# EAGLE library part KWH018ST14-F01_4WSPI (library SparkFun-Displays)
Fomike KWH018ST14-F01 TFT LCD Module Using 4WSPI Interface 128 x 160 pixel 18-bit color depth LCD module with LED backlight. This part uses the 4WSPI interface, though several other interface options are broken out in the FPC cable. Use the other corresponding devices for 3WSPI, and 8/9/16/18 bit parallel. Note: PROD_ID corresponds to the connector and the second ID (PROD_ID1 = LCD-14196) corresponds to the actual module Variants: Bottom - For use with bottom-contact FPC connectors Top - For use with top-contact FPC connectors SparkFun Products:

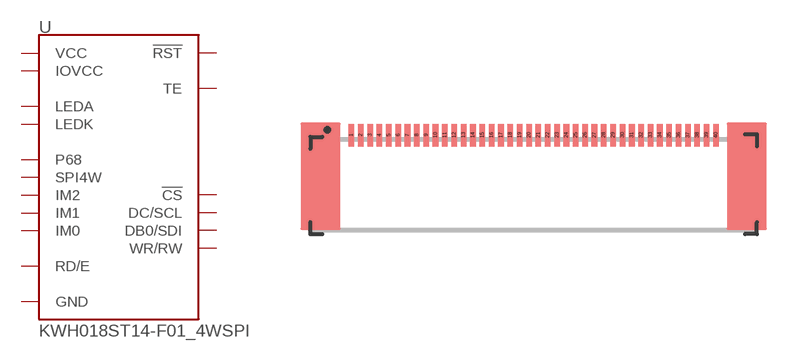
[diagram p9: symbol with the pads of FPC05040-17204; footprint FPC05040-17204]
Designator prefix U

## KWH018ST14-F01_4WSPI-TOP (PROD_ID: CONN-14082; PROD_ID1: LCD-14196)  [FPC05040-17204]
1  GND
6  GND
7  IM0
8  IM1
9  IM2
10  P68
11  SPI4W
12  !CS
13  DC/SCL
14  WR/RW
15  RD/E
16  DB0/SDI
17  GND
18  GND
19  GND
20  GND
21  GND
22  GND
23  GND
24  GND
25  GND
26  GND
27  GND
28  GND
29  GND
30  GND
31  GND
32  GND
33  GND
34  TE
35  IOVCC
36  VCC
37  !RST
38  GND
39  LEDK
40  LEDA

## KWH018ST14-F01_4WSPI-BOTTOM (PROD_ID: CONN-14082; PROD_ID1: LCD-14196)  [FPC05040-17204]
1  LEDA
2  LEDK
3  GND
4  !RST
5  VCC
6  IOVCC
7  TE
8  GND
9  GND
10  GND
11  GND
12  GND
13  GND
14  GND
15  GND
16  GND
17  GND
18  GND
19  GND
20  GND
21  GND
22  GND
23  GND
24  GND
25  DB0/SDI
26  RD/E
27  WR/RW
28  DC/SCL
29  !CS
30  SPI4W
31  P68
32  IM2
33  IM1
34  IM0
35  GND
40  GND

## Footprint FPC05040-17204 (pad centres in mm)
FPC05040 - This is a 0.5mm pitch FPC connector with 40 positions Specifications: Pin count: 40 Pin pitch: 0.5mm Area: 20mm x 5mm Datasheet referenced for footprint Example device(s):
smd 0.3 x 1.2: 1 -9.75,0.6; 2 -9.25,0.6; 3 -8.75,0.6; 4 -8.25,0.6; 5 -7.75,0.6; 6 -7.25,0.6; 7 -6.75,0.6; 8 -6.25,0.6; 9 -5.75,0.6; 10 -5.25,0.6; 11 -4.75,0.6; 12 -4.25,0.6; 13 -3.75,0.6; 14 -3.25,0.6; 15 -2.75,0.6; 16 -2.25,0.6; 17 -1.75,0.6; 18 -1.25,0.6; 19 -0.75,0.6; 20 -0.25,0.6; 21 0.25,0.6; 22 0.75,0.6; 23 1.25,0.6; 24 1.75,0.6; 25 2.25,0.6; 26 2.75,0.6; 27 3.25,0.6; 28 3.75,0.6; 29 4.25,0.6; 30 4.75,0.6; 31 5.25,0.6; 32 5.75,0.6; 33 6.25,0.6; 34 6.75,0.6; 35 7.25,0.6; 36 7.75,0.6; 37 8.25,0.6; 38 8.75,0.6; 39 9.25,0.6; 40 9.75,0.6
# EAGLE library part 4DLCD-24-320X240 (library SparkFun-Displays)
4D LCD 4DLCD-24320240-IPS - 2.4" 240x320 TFT LCD 4-wire SPI capable TFT display. 36.72 x 48.96mm active area

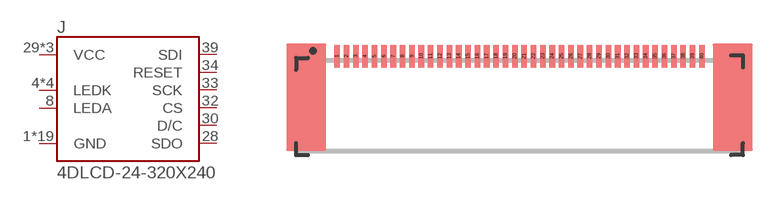
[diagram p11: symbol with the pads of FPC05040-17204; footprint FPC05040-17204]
Designator prefix J

## 4DLCD-24-320X240 (PROD_ID: LCD-16014; PROD_ID1: CONN-14082; VALUE: 2.4" TFT)  [FPC05040-17204]
1  GND
4  LEDK
5  LEDK
6  LEDK
7  LEDK
8  LEDA
11  GND
12  GND
13  GND
14  GND
15  GND
16  GND
17  GND
18  GND
19  GND
20  GND
21  GND
22  GND
23  GND
24  GND
25  GND
26  GND
27  GND
28  SDO
29  VCC
30  D/C
31  VCC
32  CS
33  SCK
34  RESET
38  VCC
39  SDI
40  GND

## Footprint FPC05040-17204 (pad centres in mm)
FPC05040 - This is a 0.5mm pitch FPC connector with 40 positions Specifications: Pin count: 40 Pin pitch: 0.5mm Area: 20mm x 5mm Datasheet referenced for footprint Example device(s):
smd 0.3 x 1.2: 1 -9.75,0.6; 2 -9.25,0.6; 3 -8.75,0.6; 4 -8.25,0.6; 5 -7.75,0.6; 6 -7.25,0.6; 7 -6.75,0.6; 8 -6.25,0.6; 9 -5.75,0.6; 10 -5.25,0.6; 11 -4.75,0.6; 12 -4.25,0.6; 13 -3.75,0.6; 14 -3.25,0.6; 15 -2.75,0.6; 16 -2.25,0.6; 17 -1.75,0.6; 18 -1.25,0.6; 19 -0.75,0.6; 20 -0.25,0.6; 21 0.25,0.6; 22 0.75,0.6; 23 1.25,0.6; 24 1.75,0.6; 25 2.25,0.6; 26 2.75,0.6; 27 3.25,0.6; 28 3.75,0.6; 29 4.25,0.6; 30 4.75,0.6; 31 5.25,0.6; 32 5.75,0.6; 33 6.25,0.6; 34 6.75,0.6; 35 7.25,0.6; 36 7.75,0.6; 37 8.25,0.6; 38 8.75,0.6; 39 9.25,0.6; 40 9.75,0.6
